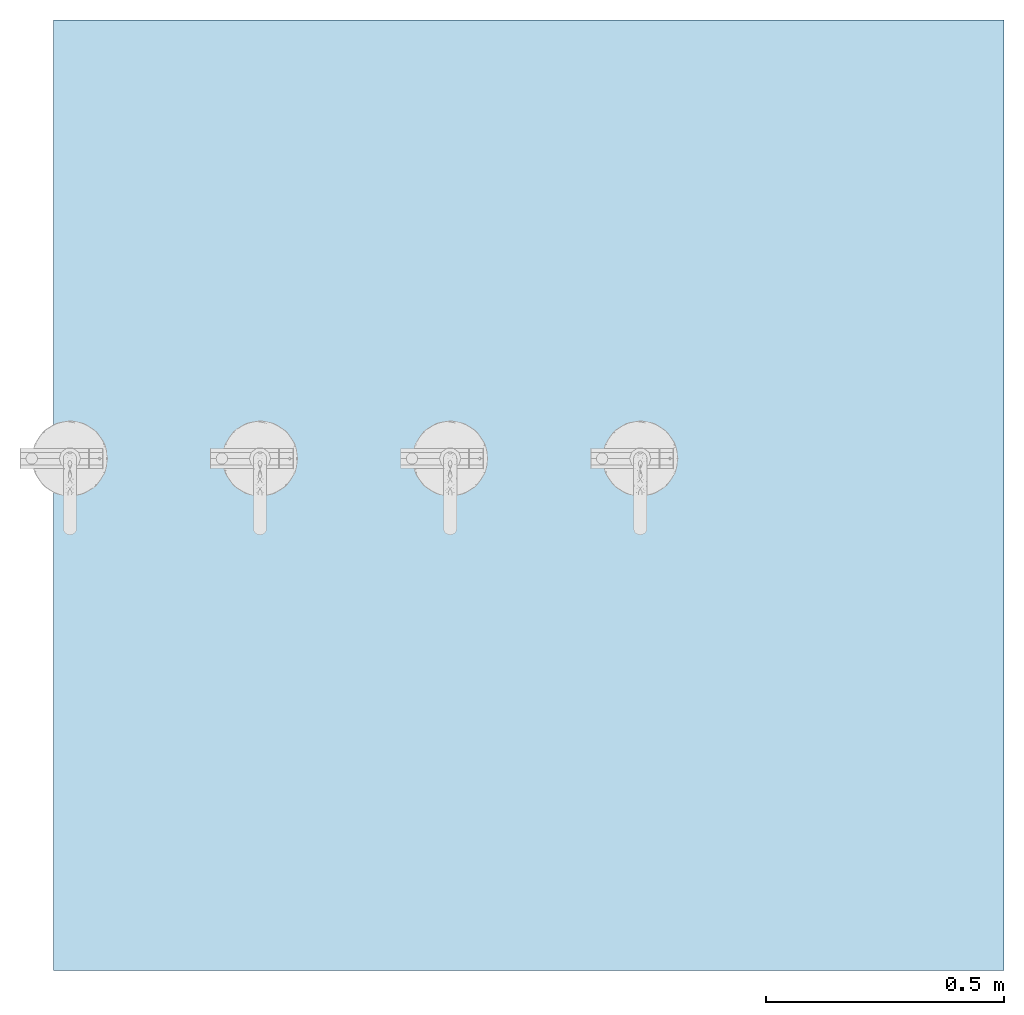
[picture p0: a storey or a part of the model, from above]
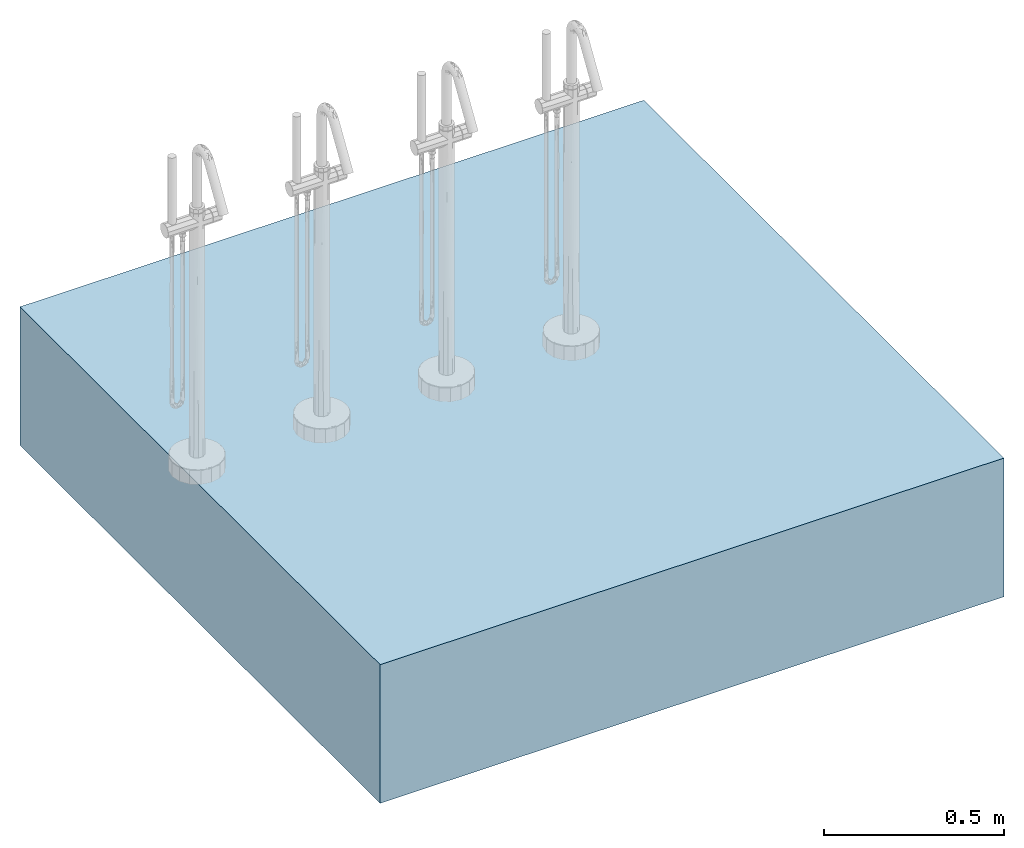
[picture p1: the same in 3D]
Properties of the parts of a building model (IFC2X3)

# File
Description: ViewDefinition [CoordinationView_V2.0]
File name: Project Number
Time: 2023-02-08T09:36:43
Written by: The EXPRESS Data Manager Version 5.02.0100.07 : 28 Aug 2013
Made in: 20220517_1515(x64) - Exporter 20.2.90.12 - Alternate UI 20.2.90.12
Comment: STEP Physical File produced by: The EXPRESS Data Manager Version 5.02.0100.07 : 28 Aug 2013 * Module: EDMstepFileFactory/EDMstandAlone * Creation date: Wed Feb 08 09:36:43 2023 * Host: LAPTOP-F3NQTQR2 * Database: C:\Users\DIANEB~1\AppData\Local\Temp\e4dc3c1c-7e4c-4369-a995-91f15f990dc4\cd3647af-e8c4-471d-aec3-e38fe728aa28\ifc * Database version: 5507 * Database creation date: Wed Feb 08 09:36:38 2023 * Schema: IFC2X3 * Model: DataRepository.ifc * Model creation date: Wed Feb 08 09:36:38 2023 * Header model: DataRepository.ifc_HeaderModel * Header model creation date: Wed Feb 08 09:36:39 2023 * EDMuser: sdai-user * EDMgroup: sdai-group * License ID and type: 5605 : Permanent license. Expiry date: * EDMstepFileFactory options: 020000

# IfcProject, Project Number
LongName: Project Name; Phase: Awaiting Approval

# IfcSite, Default
RefLatitude: 51, 30, 23, 112487; RefLongitude: 0, -7, -37, -956022; RefElevation: 0 mm

# IfcBuilding, n/a
LongName: n/a
Pset_BuildingCommon - NumberOfStoreys: 1
Pset_ProductRequirements - Category: Project Information

# IfcBuildingStorey: Level:Circle Head - Project Datum, Level 0
In: n/a
LongName: Level 0; Elevation: 0 mm
Pset_AirSideSystemInformation - Name: Level 0
Pset_ProductRequirements - Name: Level 0; Category: Levels

# IfcDistributionPort (8)
Description: Flow; FlowDirection: SOURCE
Name
2 x Port_421673
2 x Port_432130
2 x Port_432142
2 x Port_432155

# IfcFlowTerminal: DBLTD_Duten_BthMxrTapsWithShwrAndHndSprys_D412:Brushed Brass, DBLTD_Duten_BthMxrTapsWithShwrAndHndSprys_D412:Brushed Brass:432130
In: Level 0
Material: DBLTD_Duten_Metal_BrushedBrass
Pset_DistributionFlowElementCommon - Reference: Brushed Brass; sets with these values: 2
Pset_ElementShading - Color: Brushed Brass
Pset_ManufacturerTypeInformation - ModelReference: Brushed Brass; Manufacturer: contact@duten.fr
Pset_ProductRequirements - Name: Bath Mixer Tap with Shower Hose; Category: Plumbing Fixtures

# IfcFlowTerminal: DBLTD_Duten_BthMxrTapsWithShwrAndHndSprys_D412:Brushed Stainless Steel, DBLTD_Duten_BthMxrTapsWithShwrAndHndSprys_D412:Brushed Stainless Steel:421673
In: Level 0
Material: DBLTD_Duten_Metal_BrushedStainlessSteel
Pset_DistributionFlowElementCommon - Reference: Brushed Stainless Steel; sets with these values: 2
Pset_ElementShading - Color: Brushed Stainless Steel
Pset_ManufacturerTypeInformation - ModelReference: Brushed Stainless Steel; Manufacturer: contact@duten.fr
Pset_ProductRequirements - Name: Bath Mixer Tap with Shower Hose; Category: Plumbing Fixtures

# IfcFlowTerminal: DBLTD_Duten_BthMxrTapsWithShwrAndHndSprys_D412:Chrome, DBLTD_Duten_BthMxrTapsWithShwrAndHndSprys_D412:Chrome:432142
In: Level 0
Material: DBLTD_Duten_Metal_Chrome
Pset_DistributionFlowElementCommon - Reference: Chrome; sets with these values: 2
Pset_ElementShading - Color: Chrome
Pset_ManufacturerTypeInformation - ModelReference: Chrome; Manufacturer: contact@duten.fr
Pset_ProductRequirements - Name: Bath Mixer Tap with Shower Hose; Category: Plumbing Fixtures

# IfcFlowTerminal: DBLTD_Duten_BthMxrTapsWithShwrAndHndSprys_D412:Matte Black, DBLTD_Duten_BthMxrTapsWithShwrAndHndSprys_D412:Matte Black:432155
In: Level 0
Material: DBLTD_Duten_Metal_MatteBlack
Pset_DistributionFlowElementCommon - Reference: Matte Black; sets with these values: 2
Pset_ElementShading - Color: Matte Black
Pset_ManufacturerTypeInformation - ModelReference: Matte Black; Manufacturer: contact@duten.fr
Pset_ProductRequirements - Name: Bath Mixer Tap with Shower Hose; Category: Plumbing Fixtures

# IfcSlab: Floor:Floor-Grnd-Susp_65Scr-80Ins-100Blk-75PC, Floor:Floor-Grnd-Susp_65Scr-80Ins-100Blk-75PC:421633
In: Level 0
Type - PredefinedType: FLOOR; Material: Concrete, Sand/Cement Screed 65 mm, Rigid insulation 80 mm, Air 150 mm, Concrete Masonry, Floor Block 100 mm, Concrete, Precast 75 mm
Type - Pset_ElementShading - Roughness: 914.4 mm
Type - Pset_ProductRequirements - Category: Floors
Type - Pset_QuantityTakeOff - Reference: Floor-Grnd-Susp_65Scr-80Ins-100Blk-75PC
Type - Pset_ReinforcementBarPitchOfSlab - Reference: Floor-Grnd-Susp_65Scr-80Ins-100Blk-75PC
Type - Pset_SlabCommon - Reference: Floor-Grnd-Susp_65Scr-80Ins-100Blk-75PC; IsExternal: no; ThermalTransmittance: 0.117438 kg/K/s3
Pset_QuantityTakeOff - sets with these values: 2
Pset_SlabCommon - LoadBearing: no; PitchAngle: 0 deg
